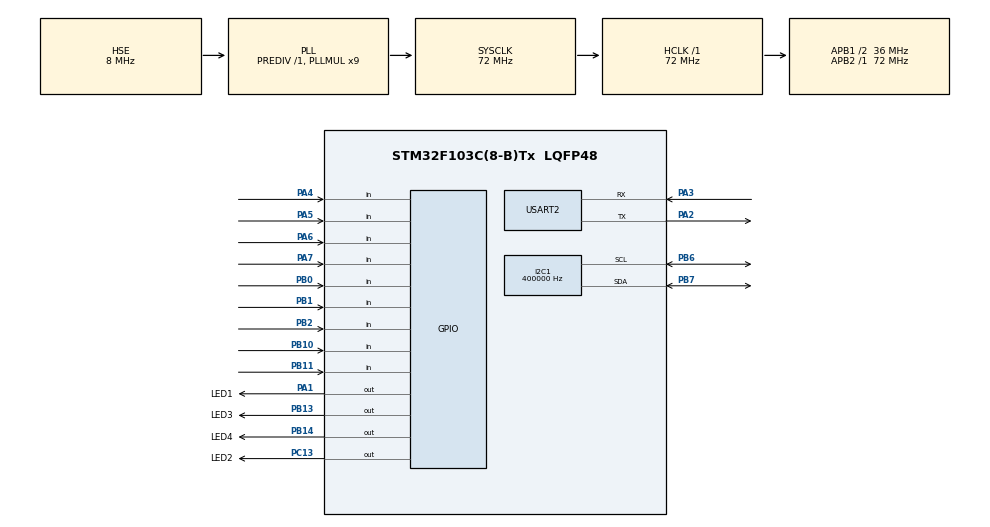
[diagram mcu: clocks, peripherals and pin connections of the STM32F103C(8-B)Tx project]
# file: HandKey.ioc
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Dma.Request0=USART2_RX
Dma.USART2_RX.0.Direction=DMA_PERIPH_TO_MEMORY
Dma.USART2_RX.0.Instance=DMA1_Channel6
Dma.USART2_RX.0.MemDataAlignment=DMA_MDATAALIGN_BYTE
Dma.USART2_RX.0.MemInc=DMA_MINC_ENABLE
Dma.USART2_RX.0.Mode=DMA_NORMAL
Dma.USART2_RX.0.PeriphDataAlignment=DMA_PDATAALIGN_BYTE
Dma.USART2_RX.0.PeriphInc=DMA_PINC_DISABLE
Dma.USART2_RX.0.Priority=DMA_PRIORITY_LOW
I2C1.ClockSpeed=400000
I2C1.I2C_Mode=I2C_Fast
Mcu.Family=STM32F1
Mcu.Name=STM32F103C(8-B)Tx
Mcu.Package=LQFP48
NVIC.DMA1_Channel6_IRQn=true\:0\:0\:false\:false\:true\:false\:true\:true
NVIC.PriorityGroup=NVIC_PRIORITYGROUP_4
NVIC.TIM2_IRQn=true\:0\:0\:false\:false\:true\:true\:true\:true
NVIC.TIM3_IRQn=true\:0\:0\:false\:false\:true\:true\:true\:true
NVIC.TIM4_IRQn=true\:0\:0\:false\:false\:true\:true\:true\:true
NVIC.USART2_IRQn=true\:0\:0\:false\:false\:true\:true\:true\:true
PA1.GPIO_Label=LED1
PA1.GPIO_ModeDefaultOutputPP=GPIO_MODE_OUTPUT_PP
PA1.GPIO_PuPd=GPIO_NOPULL
PA1.GPIO_Speed=GPIO_SPEED_FREQ_MEDIUM
PA1.PinState=GPIO_PIN_SET
PA1.Signal=GPIO_Output
PA13.Mode=Serial_Wire
PA13.Signal=SYS_JTMS-SWDIO
PA14.Mode=Serial_Wire
PA14.Signal=SYS_JTCK-SWCLK
PA2.Mode=Asynchronous
PA2.Signal=USART2_TX
PA3.Mode=Asynchronous
PA3.Signal=USART2_RX
PA4.GPIO_Mode=GPIO_MODE_INPUT
PA4.GPIO_PuPd=GPIO_PULLUP
PA4.Signal=GPIO_Input
PA5.GPIO_Mode=GPIO_MODE_INPUT
PA5.GPIO_PuPd=GPIO_PULLUP
PA5.Signal=GPIO_Input
PA6.GPIO_Mode=GPIO_MODE_INPUT
PA6.GPIO_PuPd=GPIO_PULLUP
PA6.Signal=GPIO_Input
PA7.GPIO_Mode=GPIO_MODE_INPUT
PA7.GPIO_PuPd=GPIO_PULLUP
PA7.Signal=GPIO_Input
PB0.GPIO_Mode=GPIO_MODE_INPUT
PB0.GPIO_PuPd=GPIO_PULLUP
PB0.Signal=GPIO_Input
PB1.GPIO_Mode=GPIO_MODE_INPUT
PB1.GPIO_PuPd=GPIO_PULLUP
PB1.Signal=GPIO_Input
PB10.GPIO_Mode=GPIO_MODE_INPUT
PB10.GPIO_PuPd=GPIO_PULLUP
PB10.Signal=GPIO_Input
PB11.GPIO_Mode=GPIO_MODE_INPUT
PB11.GPIO_PuPd=GPIO_PULLUP
PB11.Signal=GPIO_Input
PB13.GPIO_Label=LED3
PB13.GPIO_ModeDefaultOutputPP=GPIO_MODE_OUTPUT_PP
PB13.GPIO_PuPd=GPIO_NOPULL
PB13.GPIO_Speed=GPIO_SPEED_FREQ_MEDIUM
PB13.PinState=GPIO_PIN_SET
PB13.Signal=GPIO_Output
PB14.GPIO_Label=LED4
PB14.GPIO_ModeDefaultOutputPP=GPIO_MODE_OUTPUT_PP
PB14.GPIO_PuPd=GPIO_NOPULL
PB14.GPIO_Speed=GPIO_SPEED_FREQ_MEDIUM
PB14.PinState=GPIO_PIN_SET
PB14.Signal=GPIO_Output
PB2.GPIO_Mode=GPIO_MODE_INPUT
PB2.GPIO_PuPd=GPIO_PULLUP
PB2.Signal=GPIO_Input
PB6.Mode=I2C
PB6.Signal=I2C1_SCL
PB7.Mode=I2C
PB7.Signal=I2C1_SDA
PC13-TAMPER-RTC.GPIO_Label=LED2
PC13-TAMPER-RTC.GPIO_ModeDefaultOutputPP=GPIO_MODE_OUTPUT_PP
PC13-TAMPER-RTC.GPIO_PuPd=GPIO_NOPULL
PC13-TAMPER-RTC.GPIO_Speed=GPIO_SPEED_FREQ_MEDIUM
PC13-TAMPER-RTC.PinState=GPIO_PIN_SET
PC13-TAMPER-RTC.Signal=GPIO_Output
PD0-OSC_IN.Mode=HSE-External-Oscillator
PD0-OSC_IN.Signal=RCC_OSC_IN
PD1-OSC_OUT.Mode=HSE-External-Oscillator
PD1-OSC_OUT.Signal=RCC_OSC_OUT
ProjectManager.HeapSize=0x200
ProjectManager.StackSize=0x400
ProjectManager.TargetToolchain=MDK-ARM V5.32
RCC.AHBFreq_Value=72000000
RCC.APB1CLKDivider=RCC_HCLK_DIV2
RCC.APB1Freq_Value=36000000
RCC.APB1TimFreq_Value=72000000
RCC.APB2Freq_Value=72000000
RCC.APB2TimFreq_Value=72000000
RCC.HCLKFreq_Value=72000000
RCC.PLLMUL=RCC_PLL_MUL9
RCC.PLLSourceVirtual=RCC_PLLSOURCE_HSE
RCC.SYSCLKFreq_VALUE=72000000
RCC.SYSCLKSource=RCC_SYSCLKSOURCE_PLLCLK
RCC.USBFreq_Value=72000000
TIM2.Period=250-1
TIM2.Prescaler=7200-1
TIM3.Period=500-1
TIM3.Prescaler=7200-1
TIM4.Period=10000-1
TIM4.Prescaler=7200-1
USART2.VirtualMode=VM_ASYNC
VP_TIM2_VS_ClockSourceINT.Mode=Internal
VP_TIM3_VS_ClockSourceINT.Mode=Internal
VP_TIM4_VS_ClockSourceINT.Mode=Internal
board=custom

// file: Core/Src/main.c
/* USER CODE BEGIN Header */
/**
  ******************************************************************************
  * @file           : main.c
  * @brief          : Main program body
  ******************************************************************************
  * @attention
  *
  * Copyright (c) 2025 STMicroelectronics.
  * All rights reserved.
  *
  * This software is licensed under terms that can be found in the LICENSE file
  * in the root directory of this software component.
  * If no LICENSE file comes with this software, it is provided AS-IS.
  *
  ******************************************************************************
  */
/* USER CODE END Header */
#include "main.h"

/* USER CODE BEGIN Includes */
#include "APP.h"
/* USER CODE END Includes */

I2C_HandleTypeDef hi2c1;

TIM_HandleTypeDef htim2;
TIM_HandleTypeDef htim3;
TIM_HandleTypeDef htim4;

UART_HandleTypeDef huart2;
DMA_HandleTypeDef hdma_usart2_rx;

void SystemClock_Config(void);
static void MX_GPIO_Init(void);
static void MX_DMA_Init(void);
static void MX_I2C1_Init(void);
static void MX_USART2_UART_Init(void);
static void MX_TIM2_Init(void);
static void MX_TIM3_Init(void);
static void MX_TIM4_Init(void);

int main(void)
{

  /* MCU Configuration--------------------------------------------------------*/

  /* Reset of all peripherals, Initializes the Flash interface and the Systick. */
  HAL_Init();

  /* Configure the system clock */
  SystemClock_Config();

  /* Initialize all configured peripherals */
  MX_GPIO_Init();
  MX_DMA_Init();
  MX_I2C1_Init();
  MX_USART2_UART_Init();
  MX_TIM2_Init();
  MX_TIM3_Init();
  MX_TIM4_Init();
  /* USER CODE BEGIN 2 */
	APP_Init();
	APP_Execute();
  /* USER CODE END 2 */

  /* Infinite loop */
  while (1)
  {

  }
}

void SystemClock_Config(void)
{
  RCC_OscInitTypeDef RCC_OscInitStruct = {0};
  RCC_ClkInitTypeDef RCC_ClkInitStruct = {0};

  /** Initializes the RCC Oscillators according to the specified parameters
  * in the RCC_OscInitTypeDef structure.
  */
  RCC_OscInitStruct.OscillatorType = RCC_OSCILLATORTYPE_HSE;
  RCC_OscInitStruct.HSEState = RCC_HSE_ON;
  RCC_OscInitStruct.HSEPredivValue = RCC_HSE_PREDIV_DIV1;
  RCC_OscInitStruct.HSIState = RCC_HSI_ON;
  RCC_OscInitStruct.PLL.PLLState = RCC_PLL_ON;
  RCC_OscInitStruct.PLL.PLLSource = RCC_PLLSOURCE_HSE;
  RCC_OscInitStruct.PLL.PLLMUL = RCC_PLL_MUL9;
  if (HAL_RCC_OscConfig(&RCC_OscInitStruct) != HAL_OK)
  {
    Error_Handler();
  }

  /** Initializes the CPU, AHB and APB buses clocks
  */
  RCC_ClkInitStruct.ClockType = RCC_CLOCKTYPE_HCLK|RCC_CLOCKTYPE_SYSCLK
                              |RCC_CLOCKTYPE_PCLK1|RCC_CLOCKTYPE_PCLK2;
  RCC_ClkInitStruct.SYSCLKSource = RCC_SYSCLKSOURCE_PLLCLK;
  RCC_ClkInitStruct.AHBCLKDivider = RCC_SYSCLK_DIV1;
  RCC_ClkInitStruct.APB1CLKDivider = RCC_HCLK_DIV2;
  RCC_ClkInitStruct.APB2CLKDivider = RCC_HCLK_DIV1;

  if (HAL_RCC_ClockConfig(&RCC_ClkInitStruct, FLASH_LATENCY_2) != HAL_OK)
  {
    Error_Handler();
  }
}

static void MX_I2C1_Init(void)
{

  hi2c1.Instance = I2C1;
  hi2c1.Init.ClockSpeed = 400000;
  hi2c1.Init.DutyCycle = I2C_DUTYCYCLE_2;
  hi2c1.Init.OwnAddress1 = 0;
  hi2c1.Init.AddressingMode = I2C_ADDRESSINGMODE_7BIT;
  hi2c1.Init.DualAddressMode = I2C_DUALADDRESS_DISABLE;
  hi2c1.Init.OwnAddress2 = 0;
  hi2c1.Init.GeneralCallMode = I2C_GENERALCALL_DISABLE;
  hi2c1.Init.NoStretchMode = I2C_NOSTRETCH_DISABLE;
  if (HAL_I2C_Init(&hi2c1) != HAL_OK)
  {
    Error_Handler();
  }

}

static void MX_TIM2_Init(void)
{

  TIM_ClockConfigTypeDef sClockSourceConfig = {0};
  TIM_MasterConfigTypeDef sMasterConfig = {0};

  htim2.Instance = TIM2;
  htim2.Init.Prescaler = 7200-1;
  htim2.Init.CounterMode = TIM_COUNTERMODE_UP;
  htim2.Init.Period = 250-1;
  htim2.Init.ClockDivision = TIM_CLOCKDIVISION_DIV1;
  htim2.Init.AutoReloadPreload = TIM_AUTORELOAD_PRELOAD_DISABLE;
  if (HAL_TIM_Base_Init(&htim2) != HAL_OK)
  {
    Error_Handler();
  }
  sClockSourceConfig.ClockSource = TIM_CLOCKSOURCE_INTERNAL;
  if (HAL_TIM_ConfigClockSource(&htim2, &sClockSourceConfig) != HAL_OK)
  {
    Error_Handler();
  }
  sMasterConfig.MasterOutputTrigger = TIM_TRGO_RESET;
  sMasterConfig.MasterSlaveMode = TIM_MASTERSLAVEMODE_DISABLE;
  if (HAL_TIMEx_MasterConfigSynchronization(&htim2, &sMasterConfig) != HAL_OK)
  {
    Error_Handler();
  }

}

static void MX_TIM3_Init(void)
{

  TIM_ClockConfigTypeDef sClockSourceConfig = {0};
  TIM_MasterConfigTypeDef sMasterConfig = {0};

  htim3.Instance = TIM3;
  htim3.Init.Prescaler = 7200-1;
  htim3.Init.CounterMode = TIM_COUNTERMODE_UP;
  htim3.Init.Period = 500-1;
  htim3.Init.ClockDivision = TIM_CLOCKDIVISION_DIV1;
  htim3.Init.AutoReloadPreload = TIM_AUTORELOAD_PRELOAD_DISABLE;
  if (HAL_TIM_Base_Init(&htim3) != HAL_OK)
  {
    Error_Handler();
  }
  sClockSourceConfig.ClockSource = TIM_CLOCKSOURCE_INTERNAL;
  if (HAL_TIM_ConfigClockSource(&htim3, &sClockSourceConfig) != HAL_OK)
  {
    Error_Handler();
  }
  sMasterConfig.MasterOutputTrigger = TIM_TRGO_RESET;
  sMasterConfig.MasterSlaveMode = TIM_MASTERSLAVEMODE_DISABLE;
  if (HAL_TIMEx_MasterConfigSynchronization(&htim3, &sMasterConfig) != HAL_OK)
  {
    Error_Handler();
  }

}

static void MX_TIM4_Init(void)
{

  TIM_ClockConfigTypeDef sClockSourceConfig = {0};
  TIM_MasterConfigTypeDef sMasterConfig = {0};

  htim4.Instance = TIM4;
  htim4.Init.Prescaler = 7200-1;
  htim4.Init.CounterMode = TIM_COUNTERMODE_UP;
  htim4.Init.Period = 10000-1;
  htim4.Init.ClockDivision = TIM_CLOCKDIVISION_DIV1;
  htim4.Init.AutoReloadPreload = TIM_AUTORELOAD_PRELOAD_DISABLE;
  if (HAL_TIM_Base_Init(&htim4) != HAL_OK)
  {
    Error_Handler();
  }
  sClockSourceConfig.ClockSource = TIM_CLOCKSOURCE_INTERNAL;
  if (HAL_TIM_ConfigClockSource(&htim4, &sClockSourceConfig) != HAL_OK)
  {
    Error_Handler();
  }
  sMasterConfig.MasterOutputTrigger = TIM_TRGO_RESET;
  sMasterConfig.MasterSlaveMode = TIM_MASTERSLAVEMODE_DISABLE;
  if (HAL_TIMEx_MasterConfigSynchronization(&htim4, &sMasterConfig) != HAL_OK)
  {
    Error_Handler();
  }

}

static void MX_USART2_UART_Init(void)
{

  huart2.Instance = USART2;
  huart2.Init.BaudRate = 115200;
  huart2.Init.WordLength = UART_WORDLENGTH_8B;
  huart2.Init.StopBits = UART_STOPBITS_1;
  huart2.Init.Parity = UART_PARITY_NONE;
  huart2.Init.Mode = UART_MODE_TX_RX;
  huart2.Init.HwFlowCtl = UART_HWCONTROL_NONE;
  huart2.Init.OverSampling = UART_OVERSAMPLING_16;
  if (HAL_UART_Init(&huart2) != HAL_OK)
  {
    Error_Handler();
  }

}

static void MX_DMA_Init(void)
{

  /* DMA controller clock enable */
  __HAL_RCC_DMA1_CLK_ENABLE();

  /* DMA interrupt init */
  /* DMA1_Channel6_IRQn interrupt configuration */
  HAL_NVIC_SetPriority(DMA1_Channel6_IRQn, 0, 0);
  HAL_NVIC_EnableIRQ(DMA1_Channel6_IRQn);

}

static void MX_GPIO_Init(void)
{
  GPIO_InitTypeDef GPIO_InitStruct = {0};

  /* GPIO Ports Clock Enable */
  __HAL_RCC_GPIOC_CLK_ENABLE();
  __HAL_RCC_GPIOD_CLK_ENABLE();
  __HAL_RCC_GPIOA_CLK_ENABLE();
  __HAL_RCC_GPIOB_CLK_ENABLE();

  /*Configure GPIO pin Output Level */
  HAL_GPIO_WritePin(LED2_GPIO_Port, LED2_Pin, GPIO_PIN_SET);

  /*Configure GPIO pin Output Level */
  HAL_GPIO_WritePin(GPIOA, LED1_Pin|KEY_CLK_Pin|KEY_LOAD_Pin, GPIO_PIN_SET);

  /*Configure GPIO pin Output Level */
  HAL_GPIO_WritePin(GPIOB, LED_DEG_Pin|LED3_Pin|LED4_Pin, GPIO_PIN_SET);

  /*Configure GPIO pin Output Level */
  HAL_GPIO_WritePin(BUZZER_GPIO_Port, BUZZER_Pin, GPIO_PIN_RESET);

  /*Configure GPIO pin : LED2_Pin */
  GPIO_InitStruct.Pin = LED2_Pin;
  GPIO_InitStruct.Mode = GPIO_MODE_OUTPUT_PP;
  GPIO_InitStruct.Pull = GPIO_NOPULL;
  GPIO_InitStruct.Speed = GPIO_SPEED_FREQ_MEDIUM;
  HAL_GPIO_Init(LED2_GPIO_Port, &GPIO_InitStruct);

  /*Configure GPIO pin : LED1_Pin */
  GPIO_InitStruct.Pin = LED1_Pin;
  GPIO_InitStruct.Mode = GPIO_MODE_OUTPUT_PP;
  GPIO_InitStruct.Pull = GPIO_NOPULL;
  GPIO_InitStruct.Speed = GPIO_SPEED_FREQ_MEDIUM;
  HAL_GPIO_Init(LED1_GPIO_Port, &GPIO_InitStruct);

  /*Configure GPIO pins : KEY_CLK_Pin KEY_LOAD_Pin */
  GPIO_InitStruct.Pin = KEY_CLK_Pin|KEY_LOAD_Pin;
  GPIO_InitStruct.Mode = GPIO_MODE_OUTPUT_PP;
  GPIO_InitStruct.Pull = GPIO_NOPULL;
  GPIO_InitStruct.Speed = GPIO_SPEED_FREQ_HIGH;
  HAL_GPIO_Init(GPIOA, &GPIO_InitStruct);

  /*Configure GPIO pin : KEY_DATA_Pin */
  GPIO_InitStruct.Pin = KEY_DATA_Pin;
  GPIO_InitStruct.Mode = GPIO_MODE_INPUT;
  GPIO_InitStruct.Pull = GPIO_PULLUP;
  HAL_GPIO_Init(KEY_DATA_GPIO_Port, &GPIO_InitStruct);

  /*Configure GPIO pins : LED_DEG_Pin LED3_Pin LED4_Pin */
  GPIO_InitStruct.Pin = LED_DEG_Pin|LED3_Pin|LED4_Pin;
  GPIO_InitStruct.Mode = GPIO_MODE_OUTPUT_PP;
  GPIO_InitStruct.Pull = GPIO_NOPULL;
  GPIO_InitStruct.Speed = GPIO_SPEED_FREQ_MEDIUM;
  HAL_GPIO_Init(GPIOB, &GPIO_InitStruct);

  /*Configure GPIO pin : BUZZER_Pin */
  GPIO_InitStruct.Pin = BUZZER_Pin;
  GPIO_InitStruct.Mode = GPIO_MODE_OUTPUT_PP;
  GPIO_InitStruct.Pull = GPIO_NOPULL;
  GPIO_InitStruct.Speed = GPIO_SPEED_FREQ_LOW;
  HAL_GPIO_Init(BUZZER_GPIO_Port, &GPIO_InitStruct);

}

void Error_Handler(void)
{
  __disable_irq();
  while (1)
  {
  }
}
